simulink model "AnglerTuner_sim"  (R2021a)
settings: Solver=FixedStepAuto  StartTime=0.0  StopTime=Endtime  FixedStep=Ts  RelTol=1e-3
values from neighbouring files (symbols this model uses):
  Ts = 20e-3    (= 0.02)    [AnglerTuner_main.m]
undefined symbols (not defined in the file or in its folder): DiscIntNeverNeededParam, hex2dec
libraries: arduinolib x2, arduinomotorcarrierlib x2

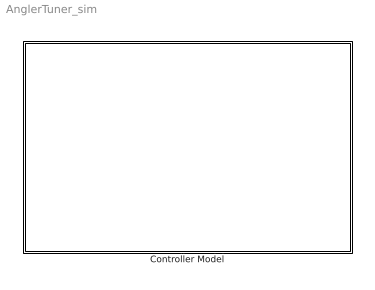
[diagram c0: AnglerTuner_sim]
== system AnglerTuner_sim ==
  Controller Model : Subsystem

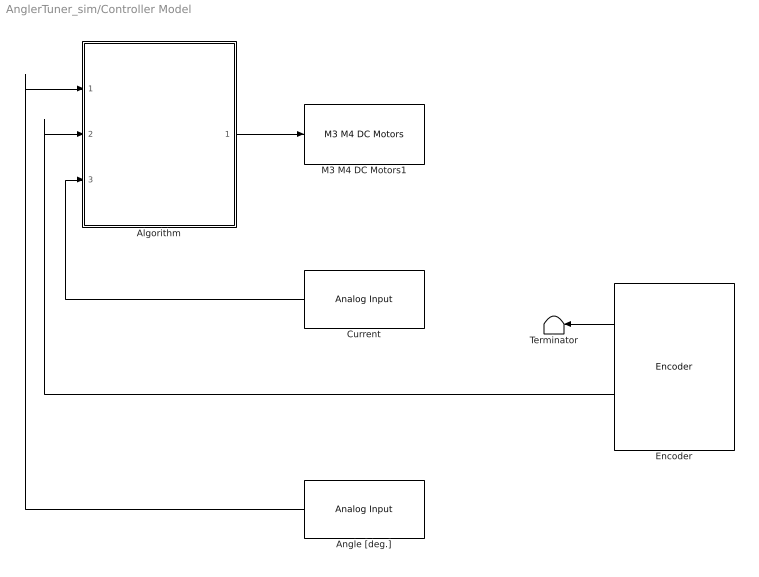
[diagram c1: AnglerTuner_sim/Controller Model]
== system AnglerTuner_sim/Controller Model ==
  Algorithm : Subsystem
  Angle [deg.] : arduinolib/Analog Input  pinNumber=1  ReadResultsOnly=off  ConversionTriggerSource=Software  ExternalTriggerType=uint32( 0 )  OutputDataType=uint16  EnableConversionCompleteNotify=off  EnableOuputStatus=off  SampleTime=Ts  blockPlatform=arduino
  Current : arduinolib/Analog Input  pinNumber=4  ReadResultsOnly=off  ConversionTriggerSource=Software  ExternalTriggerType=uint32( 0 )  OutputDataType=uint16  EnableConversionCompleteNotify=off  EnableOuputStatus=off  SampleTime=Ts  blockPlatform=arduino
  Encoder : arduinomotorcarrierlib/Encoder  SlaveAddress=uint8( hex2dec( '66' ) )  blockPlatform=ARDUINO  Encoder=2  ShowSpeed=on  ResetOption=on  SampleTime=Ts
  M3 M4 DC Motors1 : arduinomotorcarrierlib/M3 M4 DC Motors  MotorNumber=M4  forwardPinNumber=4  reversePinNumber=5
  Terminator : Terminator
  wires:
  Angle [deg.]/1 -> Algorithm/1(theta_D [-])
  Encoder/2 -> Algorithm/2(w_D [4tick/s])
  Current/1 -> Algorithm/3(i_D [-])
  Algorithm/1(u_D [-]) -> M3 M4 DC Motors1/1
  Encoder/1 -> Terminator/1

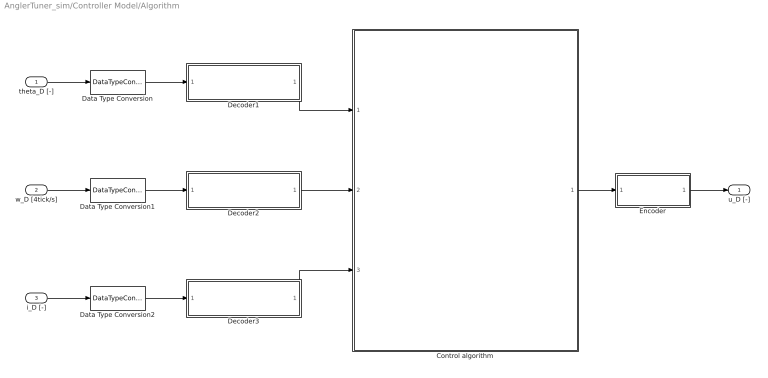
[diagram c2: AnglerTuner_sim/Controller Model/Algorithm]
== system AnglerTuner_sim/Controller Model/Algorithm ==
  theta_D [-] : Inport
  w_D [4tick/s] : Inport  Port=2
  i_D [-] : Inport  Port=3
  Control algorithm : Subsystem
  Data Type Conversion : DataTypeConversion
  Data Type Conversion1 : DataTypeConversion
  Data Type Conversion2 : DataTypeConversion
  Decoder1 : Subsystem
  Decoder2 : Subsystem
  Decoder3 : Subsystem
  Encoder : Subsystem
  u_D [-] : Outport
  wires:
  theta_D [-]/1 -> Data Type Conversion/1
  i_D [-]/1 -> Data Type Conversion2/1
  Encoder/1(u_D [-]) -> u_D [-]/1
  Control algorithm/1(u [%]) -> Encoder/1(u [%])
  Decoder1/1(theta [deg]) -> Control algorithm/1(theta [deg])
  Decoder3/1(i [A]) -> Control algorithm/3(i [A])
  Decoder2/1(N [rpm]) -> Control algorithm/2(N [rpm])
  w_D [4tick/s]/1 -> Data Type Conversion1/1
  Data Type Conversion/1 -> Decoder1/1(theta_D [-])
  Data Type Conversion1/1 -> Decoder2/1(w_D [4tick/s])
  Data Type Conversion2/1 -> Decoder3/1(i_D [-])

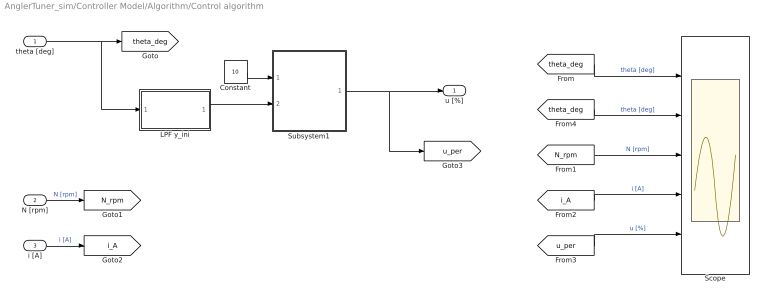
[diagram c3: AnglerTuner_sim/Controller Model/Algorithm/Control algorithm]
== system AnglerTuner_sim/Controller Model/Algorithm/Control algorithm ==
  theta [deg] : Inport
  N [rpm] : Inport  Port=2
  i [A] : Inport  Port=3
  Constant : Constant  Value=10
  LPF y_ini : MATLAB Function  TreatAsAtomicUnit=on  SystemSampleTime=Ts  mask(LPF y_ini(mask)){fc=10, Ts=Ts}
      mask prompts: fc "カットオフ周波数: fc [Hz]"; Ts "サンプリング時間: Ts [s]"
      mask help: 一次の離散時間ローパスフィルタ（LPF）です。 初期化時に入力ポートの値を用いて変数を初期化します。 fc: フィルタののカットオフ周波数 [Hz] Ts: サンプリング時間 [s] このブロックは固定のサンプル レートでのみ動作します。非周期的なトリガーを含むサブシステムでこのブロックを使用しないでください。
  Scope : Scope  NumInputPorts=5
  Subsystem1 : Subsystem
  u [%] : Outport
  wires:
  N [rpm]/1 -> [N_rpm]  "N [rpm]"
  i [A]/1 -> [i_A]  "i [A]"
  [i_A] -> Scope/4  "i [A]"
  [theta_deg] -> Scope/1  "theta [deg]"
  [N_rpm] -> Scope/3  "N [rpm]"
  [u_per] -> Scope/5  "u [%]"
  theta [deg]/1 -> LPF y_ini/1(y_k), [theta_deg]
  Constant/1 -> Subsystem1/1(SV [deg/s])
  Subsystem1/1(u [%]) -> u [%]/1, [u_per]
  LPF y_ini/1(y_f_k) -> Subsystem1/2(theta [deg])
  [theta_deg] -> Scope/2  "theta [deg]"

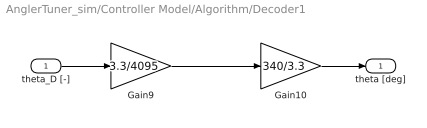
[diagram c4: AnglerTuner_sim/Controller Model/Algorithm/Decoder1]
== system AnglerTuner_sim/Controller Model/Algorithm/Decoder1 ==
  theta_D [-] : Inport
  Gain10 : Gain  Gain=340/3.3
  Gain9 : Gain  Gain=3.3/4095
  theta [deg] : Outport
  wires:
  Gain10/1 -> theta [deg]/1
  theta_D [-]/1 -> Gain9/1
  Gain9/1 -> Gain10/1

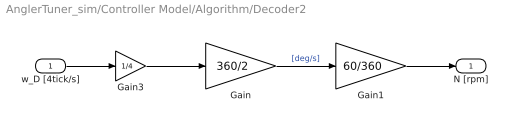
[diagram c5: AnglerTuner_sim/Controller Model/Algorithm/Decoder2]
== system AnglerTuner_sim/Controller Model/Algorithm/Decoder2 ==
  w_D [4tick/s] : Inport
  Gain : Gain  Gain=360/2
  Gain1 : Gain  Gain=60/360
  Gain3 : Gain  Gain=1/4
  N [rpm] : Outport
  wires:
  Gain1/1 -> N [rpm]/1
  w_D [4tick/s]/1 -> Gain3/1
  Gain3/1 -> Gain/1
  Gain/1 -> Gain1/1  "[deg/s]"

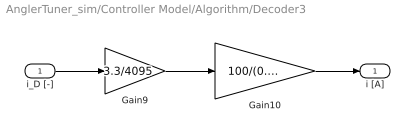
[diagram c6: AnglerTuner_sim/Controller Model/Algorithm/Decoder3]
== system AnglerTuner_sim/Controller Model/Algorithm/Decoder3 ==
  i_D [-] : Inport
  Gain10 : Gain  Gain=100/(0.24*270)
  Gain9 : Gain  Gain=3.3/4095
  i [A] : Outport
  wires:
  Gain10/1 -> i [A]/1
  i_D [-]/1 -> Gain9/1
  Gain9/1 -> Gain10/1

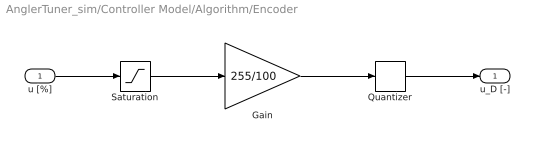
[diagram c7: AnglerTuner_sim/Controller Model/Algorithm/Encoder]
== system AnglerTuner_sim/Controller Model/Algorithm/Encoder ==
  u [%] : Inport
  Gain : Gain  Gain=255/100
  Quantizer : Quantizer  QuantizationInterval=1
  Saturation : Saturate  UpperLimit=100  LowerLimit=-100
  u_D [-] : Outport
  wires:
  u [%]/1 -> Saturation/1
  Gain/1 -> Quantizer/1
  Quantizer/1 -> u_D [-]/1
  Saturation/1 -> Gain/1

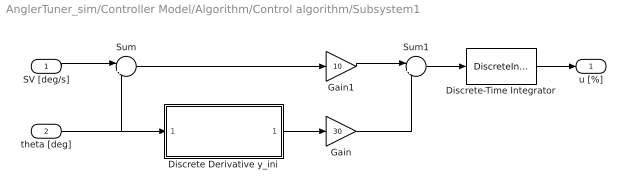
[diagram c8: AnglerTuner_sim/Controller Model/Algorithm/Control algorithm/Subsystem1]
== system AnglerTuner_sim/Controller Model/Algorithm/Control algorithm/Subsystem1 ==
  SV [deg/s] : Inport
  theta [deg] : Inport  Port=2
  Discrete Derivative y_ini : MATLAB Function  TreatAsAtomicUnit=on  SystemSampleTime=Ts  VariantControl=Choice  mask(Descrete Derivative y_ini (mask)){Ts=Ts}
      mask prompts: Ts "サンプリング時間: Ts [s]"
      mask help: 入力の離散時間微分です。 初期化時に入力ポートの値を用いて変数を初期化します。 このブロックは固定のサンプル レートでのみ動作します。非周期的なトリガーを含むサブシステムでこのブロックを使用しないでください。
  Discrete-Time Integrator : DiscreteIntegrator  SampleTime=Ts  LimitOutput=on  UpperSaturationLimit=100  LowerSaturationLimit=-100  ICPrevOutput=DiscIntNeverNeededParam  ICPrevScaledInput=DiscIntNeverNeededParam
  Gain : Gain  Gain=30
  Gain1 : Gain  Gain=10
  Sum : Sum  Inputs=|+-
  Sum1 : Sum  Inputs=|+-
  u [%] : Outport
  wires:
  SV [deg/s]/1 -> Sum/1
  theta [deg]/1 -> Discrete Derivative y_ini/1(y_k), Sum/2
  Discrete-Time Integrator/1 -> u [%]/1
  Sum/1 -> Gain1/1
  Gain1/1 -> Sum1/1
  Sum1/1 -> Discrete-Time Integrator/1
  Gain/1 -> Sum1/2
  Discrete Derivative y_ini/1(Delta_y_k) -> Gain/1

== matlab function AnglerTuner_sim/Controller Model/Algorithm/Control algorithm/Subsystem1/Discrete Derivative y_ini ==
function Delta_y_k = Dis_Derivative_y_ini(y_k, Ts)

persistent y Delta_y

if(isempty(y))
    %出力初期化
    y = y_k*ones(1, 2);
    Delta_y = zeros(1, 2);    
end

%出力計算
y(1) = y_k;
Delta_y(1) = (y(1) - y(2))/Ts;

%計算値出力
Delta_y_k = Delta_y(1);

%バッファ更新
y = circshift(y, 1, 2);
Delta_y = circshift(Delta_y, 1, 2);

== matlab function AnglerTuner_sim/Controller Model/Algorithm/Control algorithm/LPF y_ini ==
function y_f_k = LPF_y_ini(y_k, Ts, fc)

persistent y Delta_y
persistent y_f Delta_y_f a1 b0

if(isempty(y_f))
    %出力初期化
    y = y_k*ones(1, 2);
    Delta_y = zeros(1, 2);    
    %フィルタ初期化
    y_f = y_k;
    Delta_y_f = zeros(1, 2);
    %フィルタ
    Tc = 1/(2*pi*fc);
    a1 = -exp(-Ts/Tc);
    b0 = 1 - exp(-Ts/Tc);
end

%出力計算
y(1) = y_k;
Delta_y(1) = y(1) - y(2);

%フィルタ計算
Delta_y_f(1) = -a1*Delta_y_f(2) + b0*Delta_y(1);
y_f = y_f + Delta_y_f(1);

%計算値出力
y_f_k = y_f;

%バッファ更新
y = circshift(y, 1, 2);
Delta_y = circshift(Delta_y, 1, 2);
Delta_y_f = circshift(Delta_y_f, 1, 2);
